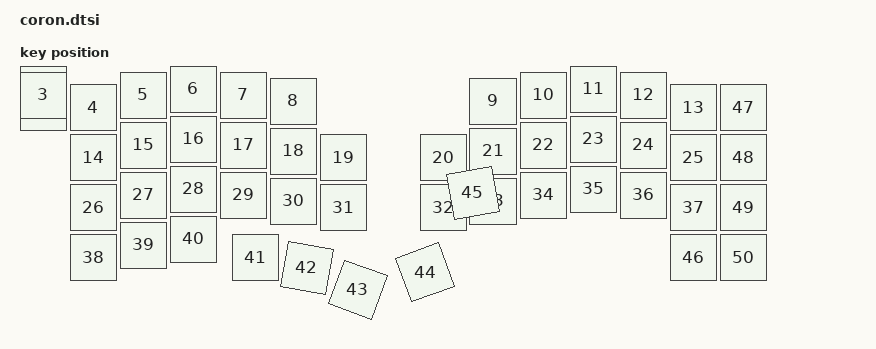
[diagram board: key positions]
#include <dt-bindings/zmk/matrix_transform.h>
#include <physical_layouts.dtsi>

/ {
    chosen {
        zmk,physical-layout = &coron_physical_layout;
    };

    coron_physical_layout: coron_physical_layout {
        compatible = "zmk,physical-layout";
        display-name = "Default";
        transform = <&default_transform>;
        kscan = <&kscan0>;

        keys  //                    w    h     x     y      rot     rx     ry
            /* Left New Column (Col 6) - Added 4 keys at start */
            = <&key_physical_attrs 100 100 (-100)   37       0      0      0>
            , <&key_physical_attrs 100 100 (-100)   12       0      0      0>
            , <&key_physical_attrs 100 100 (-100)    0       0      0      0>
            , <&key_physical_attrs 100 100 (-100)   12       0      0      0>

            /* Original Left Keys */
            , <&key_physical_attrs 100 100     0    37       0      0      0>
            , <&key_physical_attrs 100 100   100    12       0      0      0>
            , <&key_physical_attrs 100 100   200     0       0      0      0>
            , <&key_physical_attrs 100 100   300    12       0      0      0>
            , <&key_physical_attrs 100 100   400    24       0      0      0>

            , <&key_physical_attrs 100 100   800    24       0      0      0>
            , <&key_physical_attrs 100 100   900    12       0      0      0>
            , <&key_physical_attrs 100 100  1000     0       0      0      0>
            , <&key_physical_attrs 100 100  1100    12       0      0      0>
            , <&key_physical_attrs 100 100  1200    37       0      0      0>

            /* Row 1 */
            , <&key_physical_attrs 100 100     0   137       0      0      0>
            , <&key_physical_attrs 100 100   100   112       0      0      0>
            , <&key_physical_attrs 100 100   200   100       0      0      0>
            , <&key_physical_attrs 100 100   300   112       0      0      0>
            , <&key_physical_attrs 100 100   400   124       0      0      0>
            , <&key_physical_attrs 100 100   500   137       0      0      0>

            , <&key_physical_attrs 100 100   700   137       0      0      0>
            , <&key_physical_attrs 100 100   800   124       0      0      0>
            , <&key_physical_attrs 100 100   900   112       0      0      0>
            , <&key_physical_attrs 100 100  1000   100       0      0      0>
            , <&key_physical_attrs 100 100  1100   112       0      0      0>
            , <&key_physical_attrs 100 100  1200   137       0      0      0>

            /* Row 2 */
            , <&key_physical_attrs 100 100     0   237       0      0      0>
            , <&key_physical_attrs 100 100   100   212       0      0      0>
            , <&key_physical_attrs 100 100   200   200       0      0      0>
            , <&key_physical_attrs 100 100   300   212       0      0      0>
            , <&key_physical_attrs 100 100   400   224       0      0      0>
            , <&key_physical_attrs 100 100   500   237       0      0      0>

            , <&key_physical_attrs 100 100   700   237       0      0      0>
            , <&key_physical_attrs 100 100   800   224       0      0      0>
            , <&key_physical_attrs 100 100   900   212       0      0      0>
            , <&key_physical_attrs 100 100  1000   200       0      0      0>
            , <&key_physical_attrs 100 100  1100   212       0      0      0>
            , <&key_physical_attrs 100 100  1200   237       0      0      0>

            /* Row 3 */
            , <&key_physical_attrs 100 100     0   337       0      0      0>
            , <&key_physical_attrs 100 100   100   312       0      0      0>
            , <&key_physical_attrs 100 100   200   300       0      0      0>
            , <&key_physical_attrs 100 100   325   337       0      0      0>
            , <&key_physical_attrs 100 100   437   350    1000    437    350>
            , <&key_physical_attrs 100 100   550   387    2000    550    387>

            , <&key_physical_attrs 100 100   650   387 (-2000)    650    387>
            , <&key_physical_attrs 100 100   763   350 (-1000)      0    350>
            , <&key_physical_attrs 100 100  1200   337       0      0      0>

            /* Right New Column (Col 5 / Global 12) - Added 4 keys at end */
            , <&key_physical_attrs 100 100  1300    37       0      0      0>
            , <&key_physical_attrs 100 100  1300   137       0      0      0>
            , <&key_physical_attrs 100 100  1300   237       0      0      0>
            , <&key_physical_attrs 100 100  1300   337       0      0      0>
            ;
    };

    default_transform: keymap_transform_0 {
        compatible = "zmk,matrix-transform";
        columns = <13>;
        rows = <4>;
        map = <
/* L: New Col(6) + Orig(0-4) */                 /* R: Orig(7-11) + New Col(12) */
RC(0,6) RC(0,0) RC(0,1) RC(0,2) RC(0,3) RC(0,4)                 RC(0,7) RC(0,8) RC(0,9) RC(0,10
